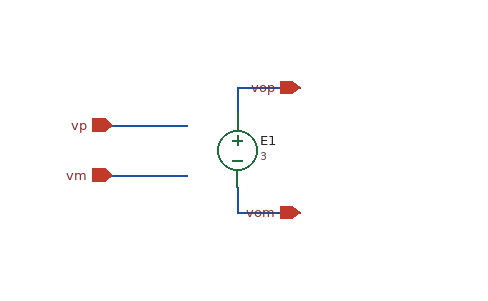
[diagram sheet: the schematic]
v {xschem version=3.4.8RC file_version=1.2}
G {}
K {}
V {}
S {}
E {}
N -40 -70 20 -70 {lab=vp}
N -40 -30 20 -30 {lab=vm}
N 60 -20 60 0 {lab=xxx}
N 60 0 110 0 {lab=xxx}
N 60 -100 60 -80 {lab=vop}
N 60 -100 110 -100 {lab=vop}
C {vcvs.sym} 60 -50 0 0 {name=E1 value=3}
C {iopin.sym} -40 -70 2 0 {name=p1 lab=vp}
C {iopin.sym} -40 -30 2 0 {name=p2 lab=vm}
C {iopin.sym} 110 -100 0 0 {name=p3 lab=vop}
C {iopin.sym} 110 0 0 0 {name=p4 lab=vom}
